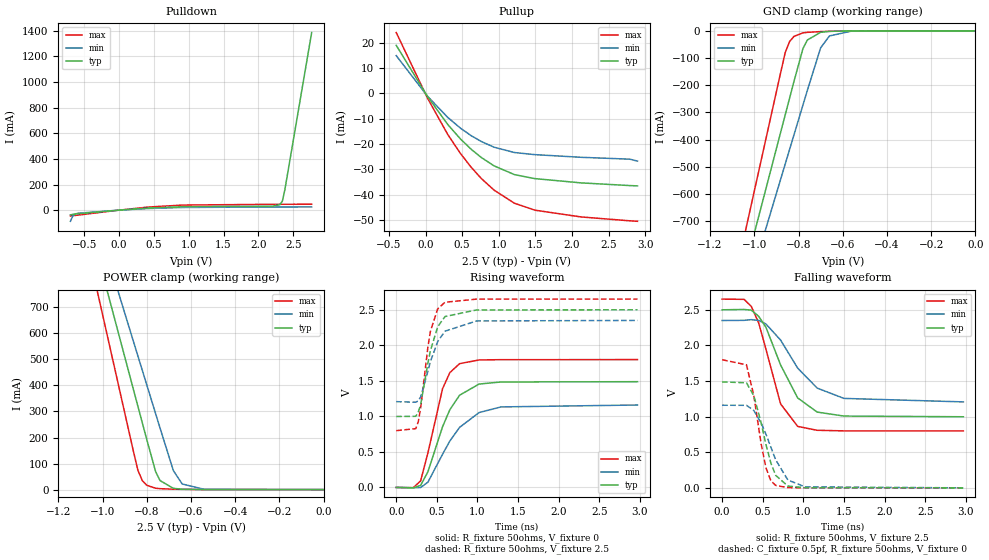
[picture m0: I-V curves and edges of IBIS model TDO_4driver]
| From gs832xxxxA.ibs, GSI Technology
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|  signals   TDO
[Model]   TDO_4driver
Model_type   3-state
Polarity   Non-Inverting
Vmeas =   1.25v
Cref  =   0pF
Rref  =   50
Vref  =   1.25v
|  variable   typ   min   max
C_comp   3.0pF   2.5pF   3.5pF
|  variable   typ   min   max
[Temperature Range]   50   0   100
|  variable   typ   min   max
[Voltage Range]   2.5   2.35   2.65
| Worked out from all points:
|   slope of the pulldown table from 0 to 0.375 V, typ, clamps not added: 24.9 ohm
|   slope of the pullup table from 0 to 0.375 V, typ, clamps not added: 25.4 ohm
|   GND clamp passes 1 mA (typ) near -0.63 V on its own axis
|   POWER clamp passes 1 mA (typ) near -0.62 V on its own axis
|   rising waveform, R_fixture 50ohms, V_fixture 0: 20-80 % time 297ps typ, 384ps min, 219ps max; typ from 0 V to 1.49 V
|   rising waveform, R_fixture 50ohms, V_fixture 2.5: 20-80 % time 164ps typ, 201ps min, 132ps max; typ from 0.998 V to 2.5 V
|   falling waveform, R_fixture 50ohms, V_fixture 2.5: 20-80 % time 344ps typ, 434ps min, 263ps max; typ from 2.5 V to 0.998 V
|   falling waveform, C_fixture 0.5pf, R_fixture 50ohms, V_fixture 0: 20-80 % time 198ps typ, 256ps min, 156ps max; typ from 1.49 V to 0 V
[Pulldown]
| voltage   I(typ)   I(min)   I(max)
-700mV    -37.33mA   -87.19mA   -46.17mA
-665mV    -32.98mA   -45.88mA   -43.75mA
-630mV    -30.5mA    -30.71mA   -41.41mA
-595mV    -28.59mA   -24.67mA   -39.15mA
0V        -75.64pA   -343.3pA   -53.94pA
420mV     16.44mA    12.63mA    24.17mA
910mV     26.44mA    20.73mA    39.52mA
2.205V    30.99mA    24.48mA    45.48mA
2.31V     43.04mA    24.56mA    45.59mA
2.345V    71.54mA    24.58mA    45.62mA
2.38V     158.7mA    24.61mA    45.65mA
2.765V    1.386A     24.87mA    45.99mA
[Pullup]
| voltage (VDDQ-Vout) I(typ)   I(min)   I(max)
-400mV    19.02mA    14.94mA    24.06mA
25mV      -1.125mA   -1.034mA   -1.743mA
305mV     -12.33mA   -9.521mA   -16.29mA
480mV     -18.07mA   -13.78mA   -23.84mA
620mV     -21.97mA   -16.62mA   -29.05mA
760mV     -25.28mA   -18.97mA   -33.55mA
935mV     -28.6mA    -21.23mA   -38.19mA
1.215V    -32.08mA   -23.35mA   -43.4mA
1.495V    -33.66mA   -24.18mA   -46.13mA
2.125V    -35.34mA   -25.23mA   -48.8mA
2.79V     -36.4mA    -25.97mA   -50.33mA
2.895V    -36.53mA   -26.74mA   -50.52mA
[GND Clamp]
| voltage   I(typ)   I(min)   I(max)
-1.5V     -2.3A      -2.224A    -2.415A
-880mV    -370.6mA   -543.1mA   -151.1mA
-860mV    -308.5mA   -489mA     -80.12mA
-840mV    -246.5mA   -434.9mA   -38.91mA
-820mV    -184.4mA   -380.9mA   -20.22mA
-780mV    -65.55mA   -272.8mA   -7.662mA
-760mV    -33.81mA   -218.9mA   -5.572mA
-700mV    -5.364mA   -62.59mA   -2.825mA
-660mV    -1.94mA    -18.77mA   -1.788mA
-560mV    -225.3uA   -949.8uA   -330.3uA
0V        -75.64pA   -343.3pA   -53.94pA
[POWER Clamp]
| voltage (VDDQ-Vout) I(typ)   I(min)   I(max)
-1.5V     2.426A     2.341A     2.554A
-860mV    382.9mA    567.6mA    145.1mA
-840mV    319.2mA    512.3mA    73.64mA
-820mV    255.5mA    457.1mA    33.99mA
-800mV    191.9mA    401.8mA    16.54mA
-760mV    68.92mA    291.3mA    5.271mA
-740mV    34.64mA    236.1mA    3.556mA
-680mV    4.879mA    73.28mA    1.644mA
-640mV    1.574mA    21.56mA    1.043mA
-540mV    157.9uA    1.034mA    211.3uA
0V        141.3pA    565.6pA    57.88pA
[Ramp]
| voltage   typ   min   max
dV/dt_r   1.33/241p   1.13/295p   1.59/197p
dV/dt_f   1.32/240p   1.13/294p   1.57/196p
R_load  =   50ohms
[Rising Waveform]
C_fixture =   0.0pf
R_fixture =   50ohms
V_fixture =   0
| Time   V(typ)   V(min)   V(max)
0s        1.363nV    5.964nV    579.4pV
210ps     -6.138mV   -5.067mV   -3.188mV
300ps     28.16mV    -2.394mV   91.34mV
390ps     220.6mV    74.09mV    487mV
570ps     853.5mV    466.7mV    1.389V
660ps     1.094V     653.6mV    1.616V
780ps     1.298V     845.5mV    1.742V
1.02ns    1.455V     1.054V     1.794V
1.29ns    1.484V     1.133V     1.798V
2.97ns    1.488V     1.16V      1.799V
[Rising Waveform]
C_fixture =   0.0pf
R_fixture =   50ohms
V_fixture =   2.5
V_fixture_min =   2.35
V_fixture_max =   2.65
| Time   V(typ)   V(min)   V(max)
0s        998.1mV    1.207V     799mV
240ps     1.001V     1.199V     827.3mV
270ps     1.055V     1.218V     918.4mV
300ps     1.162V     1.272V     1.112V
390ps     1.748V     1.636V     1.978V
420ps     1.92V      1.769V     2.194V
510ps     2.261V     2.052V     2.513V
600ps     2.405V     2.199V     2.606V
990ps     2.498V     2.343V     2.65V
2.97ns    2.5V       2.35V      2.65V
[Falling Waveform]
C_fixture =   0.0pf
R_fixture =   50ohms
V_fixture =   2.5
V_fixture_min =   2.35
V_fixture_max =   2.65
| Time   V(typ)   V(min)   V(max)
0s        2.5V       2.35V      2.65V
270ps     2.505V     2.352V     2.647V
360ps     2.495V     2.362V     2.547V
450ps     2.409V     2.351V     2.317V
540ps     2.254V     2.301V     1.946V
720ps     1.726V     2.075V     1.179V
930ps     1.263V     1.682V     863.1mV
1.17ns    1.064V     1.401V     808.4mV
1.5ns     1.008V     1.256V     800.1mV
2.97ns    998.2mV    1.207V     799mV
[Falling Waveform]
C_fixture =   0.5pf
R_fixture =   50ohms
V_fixture =   0
| Time   V(typ)   V(min)   V(max)
0s        1.488V     1.16V      1.799V
300ps     1.475V     1.159V     1.728V
390ps     1.295V     1.087V     1.3V
480ps     917.5mV    913.1mV    621.8mV
540ps     609.2mV    753.7mV    280.4mV
600ps     349.2mV    571.2mV    99.15mV
660ps     175.4mV    393.4mV    34.15mV
810ps     25.07mV    109.6mV    3.273mV
1.02ns    2.269mV    14.49mV    290uV
2.97ns    443.9nV    1.056uV    216nV
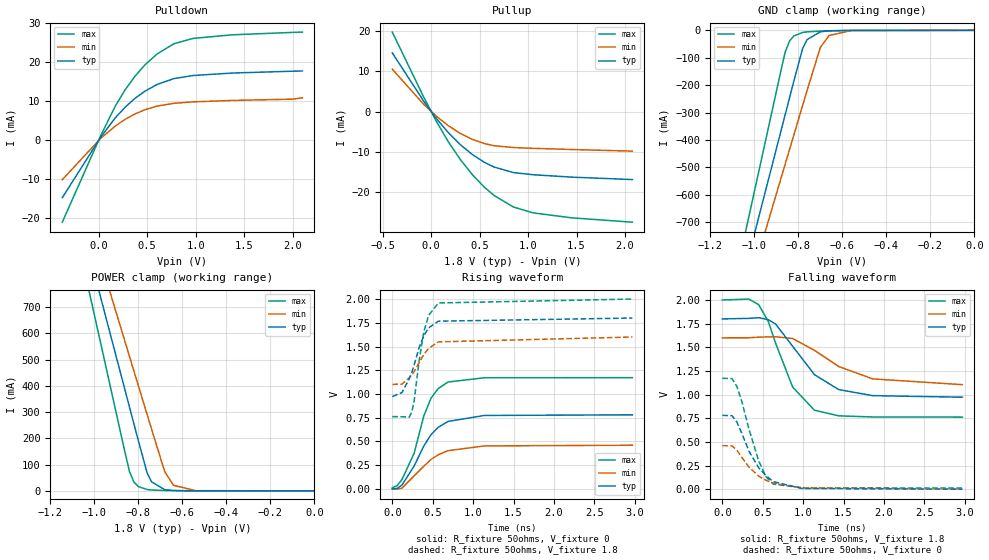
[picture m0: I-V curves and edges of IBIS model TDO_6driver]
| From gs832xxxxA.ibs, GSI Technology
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|  signals   TDO
[Model]   TDO_6driver
Model_type   3-state
Polarity   Non-Inverting
Vmeas =   0.9v
Cref  =   0pF
Rref  =   50
Vref  =   0.9v
|  variable   typ   min   max
C_comp   3.0pF   2.5pF   3.5pF
|  variable   typ   min   max
[Temperature Range]   50   0   100
|  variable   typ   min   max
[Voltage Range]   1.8   1.6   2.0
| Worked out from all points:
|   slope of the pulldown table from 0 to 0.27 V, typ, clamps not added: 32.1 ohm
|   slope of the pullup table from 0 to 0.27 V, typ, clamps not added: 35.9 ohm
|   GND clamp passes 1 mA (typ) near -0.63 V on its own axis
|   POWER clamp passes 1 mA (typ) near -0.62 V on its own axis
|   rising waveform, R_fixture 50ohms, V_fixture 0: 20-80 % time 332ps typ, 371ps min, 271ps max; typ from 0 V to 0.78 V
|   rising waveform, R_fixture 50ohms, V_fixture 1.8: 20-80 % time 206ps typ, 236ps min, 136ps max; typ from 0.973 V to 1.8 V
|   falling waveform, R_fixture 50ohms, V_fixture 1.8: 20-80 % time 469ps typ, 605ps min, 343ps max; typ from 1.8 V to 0.972 V
|   falling waveform, R_fixture 50ohms, V_fixture 0: 20-80 % time 298ps typ, 328ps min, 238ps max; typ from 0.78 V to 0 V
[Pulldown]
| voltage   I(typ)   I(min)   I(max)
-375mV    -14.68mA   -10.08mA   -20.95mA
25mV      938.5uA    601.7uA    1.425mA
175mV     5.862mA    3.733mA    8.912mA
275mV     8.525mA    5.395mA    12.99mA
375mV     10.74mA    6.743mA    16.41mA
475mV     12.54mA    7.8mA      19.25mA
600mV     14.27mA    8.743mA    22.05mA
775mV     15.79mA    9.463mA    24.7mA
975mV     16.58mA    9.834mA    26.08mA
1.375V    17.21mA    10.2mA     26.99mA
2V        17.68mA    10.53mA    27.61mA
2.1V      17.74mA    10.87mA    27.69mA
[Pullup]
| voltage (VDDQ-Vout) I(typ)   I(min)   I(max)
-400mV    14.53mA    10.5mA     19.69mA
-75mV     2.524mA    1.753mA    3.529mA
50mV      -1.592mA   -1.086mA   -2.255mA
175mV     -5.171mA   -3.477mA   -7.402mA
300mV     -8.191mA   -5.412mA   -11.86mA
425mV     -10.66mA   -6.9mA     -15.65mA
550mV     -12.6mA    -7.951mA   -18.78mA
650mV     -13.77mA   -8.487mA   -20.82mA
850mV     -15.15mA   -8.93mA    -23.69mA
1.05V     -15.67mA   -9.129mA   -25.12mA
1.45V     -16.27mA   -9.419mA   -26.36mA
2.075V    -16.87mA   -9.821mA   -27.44mA
[GND Clamp]
| voltage   I(typ)   I(min)   I(max)
-1.5V     -2.3A      -2.224A    -2.415A
-880mV    -370.6mA   -543.1mA   -151.1mA
-860mV    -308.5mA   -489mA     -80.12mA
-840mV    -246.5mA   -434.9mA   -38.91mA
-820mV    -184.4mA   -380.9mA   -20.22mA
-780mV    -65.55mA   -272.8mA   -7.662mA
-760mV    -33.81mA   -218.9mA   -5.572mA
-700mV    -5.364mA   -62.59mA   -2.825mA
-660mV    -1.94mA    -18.77mA   -1.788mA
-560mV    -225.3uA   -949.8uA   -330.3uA
0V        -80.76pA   -306.2pA   -41.52pA
[POWER Clamp]
| voltage (VDDQ-Vout) I(typ)   I(min)   I(max)
-1.5V     2.426A     2.341A     2.554A
-860mV    382.9mA    567.6mA    145.1mA
-840mV    319.2mA    512.3mA    73.64mA
-820mV    255.5mA    457.1mA    33.99mA
-800mV    191.9mA    401.8mA    16.54mA
-760mV    68.92mA    291.3mA    5.271mA
-740mV    34.64mA    236.1mA    3.556mA
-680mV    4.879mA    73.28mA    1.644mA
-640mV    1.574mA    21.56mA    1.043mA
-540mV    157.9uA    1.034mA    211.3uA
0V        110.2pA    463.8pA    44pA
[Ramp]
| voltage   typ   min   max
dV/dt_r   1.33/241p   1.13/295p   1.59/197p
dV/dt_f   1.32/240p   1.13/294p   1.57/196p
R_load  =   50ohms
[Rising Waveform]
C_fixture =   0.0pf
R_fixture =   50ohms
V_fixture =   0
| Time   V(typ)   V(min)   V(max)
0s        494.7uV    10.69uV    12.43mV
60ps      5.483mV    -2.583mV   34.25mV
120ps     40.62mV    8.367mV    98.94mV
270ps     241.4mV    138.2mV    374.8mV
390ps     451.8mV    239mV      769.2mV
480ps     572.6mV    311.1mV    957mV
570ps     650.3mV    360.8mV    1.059V
690ps     711mV      402.9mV    1.126V
1.14ns    773.9mV    453mV      1.171V
2.97ns    780.5mV    460.2mV    1.172V
[Rising Waveform]
C_fixture =   0.0pf
R_fixture =   50ohms
V_fixture =   1.8
V_fixture_min =   1.6
V_fixture_max =   2.0
| Time   V(typ)   V(min)   V(max)
0s        972.6mV    1.101V     762mV
120ps     1.015V     1.105V     760.6mV
210ps     1.162V     1.171V     756.1mV
240ps     1.224V     1.2V       809.7mV
270ps     1.303V     1.236V     921.9mV
330ps     1.484V     1.327V     1.339V
390ps     1.615V     1.417V     1.655V
450ps     1.696V     1.481V     1.829V
570ps     1.767V     1.549V     1.959V
2.97ns    1.8V       1.6V       2V
[Falling Waveform]
C_fixture =   0.0pf
R_fixture =   50ohms
V_fixture =   1.8
V_fixture_min =   1.6
V_fixture_max =   2.0
| Time   V(typ)   V(min)   V(max)
0s        1.8V       1.6V       2V
330ps     1.806V     1.601V     2.01V
450ps     1.813V     1.607V     1.951V
570ps     1.792V     1.61V      1.771V
660ps     1.746V     1.611V     1.543V
870ps     1.511V     1.593V     1.08V
1.14ns    1.211V     1.468V     834.9mV
1.44ns    1.053V     1.297V     775.3mV
1.86ns    988.8mV    1.166V     763.4mV
2.97ns    972.3mV    1.105V     762.2mV
[Falling Waveform]
C_fixture =   0.0pf
R_fixture =   50ohms
V_fixture =   0
| Time   V(typ)   V(min)   V(max)
0s        780.5mV    460.2mV    1.172V
120ps     776.8mV    458mV      1.169V
180ps     711.1mV    414.2mV    1.088V
240ps     593.5mV    338.9mV    932.4mV
330ps     401.5mV    233.5mV    634.6mV
450ps     226.9mV    137.9mV    300mV
540ps     143.1mV    94.28mV    131.5mV
630ps     80.08mV    63.8mV     54.16mV
990ps     6.031mV    14.32mV    13.67mV
2.97ns    496.2uV    25.66uV    12.43mV
